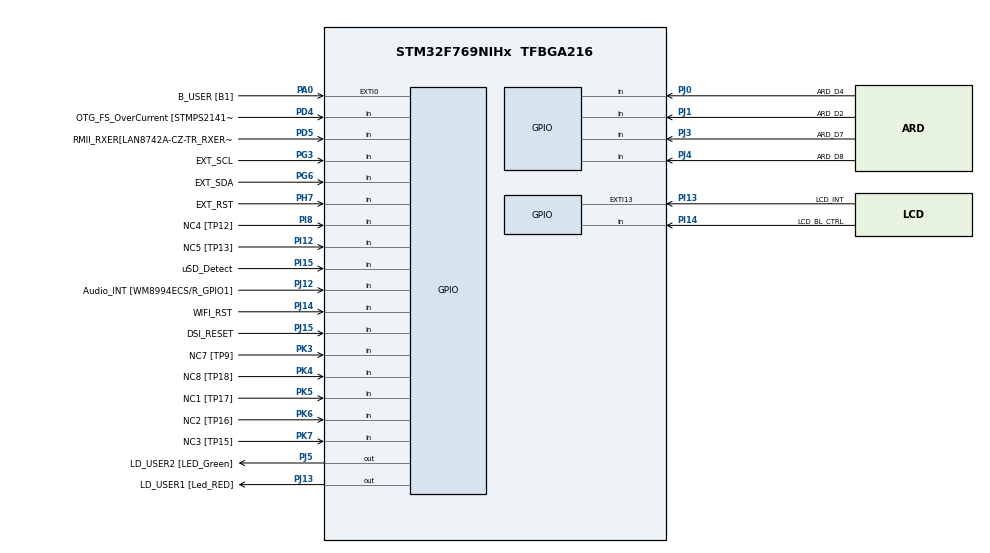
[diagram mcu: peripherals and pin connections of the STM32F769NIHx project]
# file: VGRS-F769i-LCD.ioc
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DSIHOST_CKN.GPIO_Label=DSI_CK_N
DSIHOST_CKN.Signal=DSIHOST_CKN
DSIHOST_CKP.GPIO_Label=DSI_CK_P
DSIHOST_CKP.Signal=DSIHOST_CKP
DSIHOST_D0N.GPIO_Label=DSI_D0_N
DSIHOST_D0N.Signal=DSIHOST_D0N
DSIHOST_D0P.GPIO_Label=DSI_D0_p
DSIHOST_D0P.Signal=DSIHOST_D0P
DSIHOST_D1N.GPIO_Label=DSI_D1_N
DSIHOST_D1N.Signal=DSIHOST_D1N
DSIHOST_D1P.GPIO_Label=DSI_D1_P
DSIHOST_D1P.Signal=DSIHOST_D1P
FREERTOS.Tasks01=defaultTask,24,512,StartDefaultTask,Default,NULL,Dynamic,NULL,NULL
FREERTOS.configMINIMAL_STACK_SIZE=512
Mcu.Family=STM32F7
Mcu.Name=STM32F769NIHx
Mcu.Package=TFBGA216
NVIC.PriorityGroup=NVIC_PRIORITYGROUP_4
PA0/WKUP.GPIO_Label=B_USER [B1]
PA0/WKUP.Signal=GPXTI0
PA1.GPIO_Label=RMII_REF_CLK [LAN8742A-CZ-TR_REFCLK0]
PA1.Signal=ETH_REF_CLK
PA10.GPIO_Label=VCP_RX 
PA10.Signal=USART1_RX
PA11.GPIO_Label=SPI2_NSS
PA11.Signal=SPI2_NSS
PA12.GPIO_Label=ARD_D13/SCK
PA12.GPIO_Mode=GPIO_MODE_AF_PP
PA12.GPIO_PuPd=GPIO_NOPULL
PA12.GPIO_Speed=GPIO_SPEED_FREQ_LOW
PA12.Signal=SPI2_SCK
PA13.GPIO_Label=SWDIO
PA13.Signal=SYS_JTMS-SWDIO
PA14.GPIO_Label=SWCLK
PA14.Signal=SYS_JTCK-SWCLK
PA15.GPIO_Label=CEC
PA15.Signal=CEC
PA2.GPIO_Label=RMII_MDIO [LAN8742A-CZ-TR_MDIO]
PA2.Signal=ETH_MDIO
PA3.GPIO_Label=ULPI_D0 [USB3320C-EZK_D0]
PA3.Signal=USB_OTG_HS_ULPI_D0
PA4.GPIO_Label=ARD_A1
PA4.Signal=ADCx_IN4
PA5.GPIO_Label=ULPI_CLK [USB3320C-EZK_CLKOUT]
PA5.Signal=USB_OTG_HS_ULPI_CK
PA6.GPIO_Label=ARD_A0
PA6.Signal=ADCx_IN6
PA7.GPIO_Label=RMII_CRS_DV [LAN8742A-CZ-TR_CRS_DV]
PA7.Signal=ETH_CRS_DV
PA8.GPIO_Label=CEC_CLK [TP2]
PA8.Signal=RCC_MCO_1
PA9.GPIO_Label=VCP_TX [STM32F103CBT6_PA3]
PA9.GPIO_Mode=GPIO_MODE_AF_PP
PA9.GPIO_PuPd=GPIO_NOPULL
PA9.GPIO_Speed=GPIO_SPEED_FREQ_LOW
PA9.Signal=USART1_TX
PB0.GPIO_Label=ULPI_D1 [USB3320C-EZK_D1]
PB0.Signal=USB_OTG_HS_ULPI_D1
PB1.GPIO_Label=ULPI_D2 [USB3320C-EZK_D2]
PB1.Signal=USB_OTG_HS_ULPI_D2
PB10.GPIO_Label=ULPI_D3 [USB3320C-EZK_D3]
PB10.Signal=USB_OTG_HS_ULPI_D3
PB11.GPIO_Label=ULPI_D4 [USB3320C-EZK_D4]
PB11.Signal=USB_OTG_HS_ULPI_D4
PB12.GPIO_Label=ULPI_D5 [USB3320C-EZK_D5]
PB12.Signal=USB_OTG_HS_ULPI_D5
PB13.GPIO_Label=ULPI_D6 [USB3320C-EZK_D6]
PB13.Signal=USB_OTG_HS_ULPI_D6
PB14.GPIO_Label=ARDUINO MISO/D12
PB14.GPIO_Mode=GPIO_MODE_AF_PP
PB14.GPIO_PuPd=GPIO_NOPULL
PB14.GPIO_Speed=GPIO_SPEED_FREQ_LOW
PB14.Signal=SPI2_MISO
PB15.GPIO_Label=ARDUINO MOSI/PWM/D11
PB15.GPIO_Mode=GPIO_MODE_AF_PP
PB15.GPIO_PuPd=GPIO_NOPULL
PB15.GPIO_Speed=GPIO_SPEED_FREQ_LOW
PB15.Signal=SPI2_MOSI
PB2.Signal=QUADSPI_CLK
PB3.GPIO_Label=uSD_D2
PB3.Signal=SDMMC2_D2
PB4.GPIO_Label=uSD_D3
PB4.Signal=SDMMC2_D3
PB5.GPIO_Label=ULPI_D7 [USB3320C-EZK_D7]
PB5.Signal=USB_OTG_HS_ULPI_D7
PB6.GPIO_Label=QSPI_NCS [N25Q128A13EF840E_S]
PB6.Signal=QUADSPI_BK1_NCS
PB7.GPIO_Label=AUDIO_SDA [WM8994ECS/R_SDA]
PB7.Signal=I2C4_SDA
PB8.GPIO_Label=ARDUINO SCL/D15
PB8.GPIO_Mode=GPIO_MODE_AF_OD
PB8.GPIO_PuPd=GPIO_NOPULL
PB8.GPIO_Speed=GPIO_SPEED_FREQ_LOW
PB8.Signal=I2C1_SCL
PB9.GPIO_Label=ARDUINO SDA/D14
PB9.GPIO_Mode=GPIO_MODE_AF_OD
PB9.GPIO_PuPd=GPIO_NOPULL
PB9.GPIO_Speed=GPIO_SPEED_FREQ_LOW
PB9.Signal=I2C1_SDA
PC0.GPIO_Label=ULPI_STP [USB3320C-EZK_STP]
PC0.Signal=USB_OTG_HS_ULPI_STP
PC1.GPIO_Label=RMII_MDC [LAN8742A-CZ-TR_MDC]
PC1.Signal=ETH_MDC
PC10.GPIO_Label=QSPI_D1 [MT25QL512ABB1EW9_DQ1]
PC10.Signal=QUADSPI_BK1_IO1
PC11.GPIO_Label=DFSDM_DATIN5 [TP100]
PC11.Signal=S_DATAIN5DFSDM1
PC12.GPIO_Label=WIFI_RX
PC12.Signal=UART5_TX
PC14/OSC32_IN.GPIO_Label=RCC_OSC32_IN
PC14/OSC32_IN.Signal=RCC_OSC32_IN
PC15/OSC32_OUT.GPIO_Label=RCC_OSC32_OUT
PC15/OSC32_OUT.Signal=RCC_OSC32_OUT
PC2.GPIO_Label=ARD_A2
PC2.Signal=ADCx_IN12
PC3.GPIO_Label=DFSDM_DATIN1 [TP101]
PC3.Signal=S_DATAIN1DFSDM1
PC4.GPIO_Label=RMII_RXD0 [LAN8742A-CZ-TR_RXD0]
PC4.Signal=ETH_RXD0
PC5.GPIO_Label=RMII_RXD1 [LAN8742A-CZ-TR_RXD1]
PC5.Signal=ETH_RXD1
PC6.GPIO_Label=ARDUINO TX/D1
PC6.Signal=USART6_TX
PC7.GPIO_Label=ARD_D0/RX
PC7.Signal=USART6_RX
PC8.GPIO_Label=ARD_D5/PWM
PC8.Signal=S_TIM3_CH3
PC9.GPIO_Label=QSPI_D0 [N25Q128A13EF840E_DQ0]
PC9.Signal=QUADSPI_BK1_IO0
PD0.GPIO_Label=FMC_D2 [MT48LC4M32B2B5-6A_DQ2]
PD0.Signal=FMC_D2_DA2
PD1.GPIO_Label=FMC_D3 [MT48LC4M32B2B5-6A_DQ3]
PD1.Signal=FMC_D3_DA3
PD10.GPIO_Label=FMC_D15 [MT48LC4M32B2B5-6A_DQ15]
PD10.Signal=FMC_D15_DA15
PD11.GPIO_Label=SPDIF_TX [TP20]
PD11.Signal=SAI2_SD_A
PD12.GPIO_Label=AUDIO_SCL [WM8994ECS/R_SCLK]
PD12.Signal=I2C4_SCL
PD13.GPIO_Label=QSPI_D3 [N25Q128A13EF840E_DQ3]
PD13.Signal=QUADSPI_BK1_IO3
PD14.GPIO_Label=FMC_D0 [MT48LC4M32B2B5-6A_DQ0]
PD14.Signal=FMC_D0_DA0
PD15.GPIO_Label=FMC_D1 [MT48LC4M32B2B5-6A_DQ1]
PD15.Signal=FMC_D1_DA1
PD2.GPIO_Label=WIFI_TX
PD2.Signal=UART5_RX
PD3.GPIO_Label=DFSDM_CKOUT [TP102]
PD3.Signal=S_CKOUTDFSDM1
PD4.GPIO_Label=OTG_FS_OverCurrent [STMPS2141STR_Fault]
PD4.Signal=GPIO_Input
PD5.GPIO_Label=RMII_RXER[LAN8742A-CZ-TR_RXERR]
PD5.Signal=GPIO_Input
PD6.GPIO_Label=uSD_CLK
PD6.Signal=SDMMC2_CK
PD7.GPIO_Label=uSD_CMD
PD7.Signal=SDMMC2_CMD
PD8.GPIO_Label=FMC_D13 [MT48LC4M32B2B5-6A_DQ13]
PD8.Signal=FMC_D13_DA13
PD9.GPIO_Label=FMC_D14 [MT48LC4M32B2B5-6A_DQ14]
PD9.Signal=FMC_D14_DA14
PE0.GPIO_Label=FMC_NBL0 [MT48LC4M32B2B5-6A_DQM0]
PE0.Signal=FMC_NBL0
PE1.GPIO_Label=FMC_NBL1 [MT48LC4M32B2B5-6A_DQM1]
PE1.Signal=FMC_NBL1
PE10.GPIO_Label=FMC_D7 [MT48LC4M32B2B5-6A_DQ7]
PE10.Signal=FMC_D7_DA7
PE11.GPIO_Label=FMC_D8 [MT48LC4M32B2B5-6A_DQ8]
PE11.Signal=FMC_D8_DA8
PE12.GPIO_Label=FMC_D9 [MT48LC4M32B2B5-6A_DQ9]
PE12.Signal=FMC_D9_DA9
PE13.GPIO_Label=FMC_D10 [MT48LC4M32B2B5-6A_DQ10]
PE13.Signal=FMC_D10_DA10
PE14.GPIO_Label=FMC_D11 [MT48LC4M32B2B5-6A_DQ11]
PE14.Signal=FMC_D11_DA11
PE15.GPIO_Label=FMC_D12 [MT48LC4M32B2B5-6A_DQ12]
PE15.Signal=FMC_D12_DA12
PE2.GPIO_Label=QSPI_D2 [N25Q128A13EF840E_DQ2]
PE2.Signal=QUADSPI_BK1_IO2
PE3.GPIO_Label=SAI1_SDB [WM8994ECS/R_ADCDAT1]
PE3.Signal=SAI1_SD_B
PE4.GPIO_Label=SAI1_FSA [WM8994ECS/R_LRCLK1]
PE4.Signal=SAI1_FS_A
PE5.GPIO_Label=SAI1_SCKA [WM8994ECS/R_BCLK1]
PE5.Signal=SAI1_SCK_A
PE6.GPIO_Label=SAI1_SDA [WM8994ECS/R_DACDAT1]
PE6.Signal=SAI1_SD_A
PE7.GPIO_Label=FMC_D4 [MT48LC4M32B2B5-6A_DQ4]
PE7.Signal=FMC_D4_DA4
PE8.GPIO_Label=FMC_D5 [MT48LC4M32B2B5-6A_DQ5]
PE8.Signal=FMC_D5_DA5
PE9.GPIO_Label=FMC_D6 [MT48LC4M32B2B5-6A_DQ6]
PE9.Signal=FMC_D6_DA6
PF0.GPIO_Label=FMC_A0 [MT48LC4M32B2B5-6A_A0]
PF0.Signal=FMC_A0
PF1.GPIO_Label=FMC_A1 [MT48LC4M32B2B5-6A_A1]
PF1.Signal=FMC_A1
PF10.GPIO_Label=ARDUINO A1
PF10.GPIO_Mode=GPIO_MODE_ANALOG
PF10.GPIO_PuPd=GPIO_NOPULL
PF10.Signal=ADC3_IN8
PF11.GPIO_Label=FMC_SDNRAS [MT48LC4M32B2B5-6A_RAS]
PF11.Signal=FMC_SDNRAS
PF12.GPIO_Label=FMC_A6 [MT48LC4M32B2B5-6A_A6]
PF12.Signal=FMC_A6
PF13.GPIO_Label=FMC_A7 [MT48LC4M32B2B5-6A_A7]
PF13.Signal=FMC_A7
PF14.GPIO_Label=FMC_A8 [MT48LC4M32B2B5-6A_A8]
PF14.Signal=FMC_A8
PF15.GPIO_Label=FMC_A9 [MT48LC4M32B2B5-6A_A9]
PF15.Signal=FMC_A9
PF2.GPIO_Label=FMC_A2 [MT48LC4M32B2B5-6A_A2]
PF2.Signal=FMC_A2
PF3.GPIO_Label=FMC_A3 [MT48LC4M32B2B5-6A_A3]
PF3.Signal=FMC_A3
PF4.GPIO_Label=FMC_A4 [MT48LC4M32B2B5-6A_A4]
PF4.Signal=FMC_A4
PF5.GPIO_Label=FMC_A5 [MT48LC4M32B2B5-6A_A5]
PF5.Signal=FMC_A5
PF6.GPIO_Label=ARD_D3/PWM
PF6.Signal=S_TIM10_CH1
PF7.GPIO_Label=ARD_D6/PWM
PF7.Signal=S_TIM11_CH1
PF8.GPIO_Label=ARDUINO A3
PF8.GPIO_Mode=GPIO_MODE_ANALOG
PF8.GPIO_PuPd=GPIO_NOPULL
PF8.Signal=ADC3_IN6
PF9.GPIO_Label=ARDUINO A2
PF9.GPIO_Mode=GPIO_MODE_ANALOG
PF9.GPIO_PuPd=GPIO_NOPULL
PF9.Signal=ADC3_IN7
PG0.GPIO_Label=FMC_A10 [MT48LC4M32B2B5-6A_A10]
PG0.Signal=FMC_A10
PG1.GPIO_Label=FMC_A11 [MT48LC4M32B2B5-6A_A11]
PG1.Signal=FMC_A11
PG10.GPIO_Label=uSD_D1
PG10.Signal=SDMMC2_D1
PG11.GPIO_Label=RMII_TX_EN [LAN8742A-CZ-TR_TXEN]
PG11.Signal=ETH_TX_EN
PG12.GPIO_Label=SPDIF_RX [74LVC1G04SE_4]
PG12.Signal=SPDIFRX_IN1
PG13.GPIO_Label=RMII_TXD0 [LAN8742A-CZ-TR_TXD0]
PG13.Signal=ETH_TXD0
PG14.GPIO_Label=RMII_TXD1 [LAN8742A-CZ-TR_TXD1]
PG14.Signal=ETH_TXD1
PG15.GPIO_Label=FMC_SDNCAS [MT48LC4M32B2B5-6A_CAS]
PG15.Signal=FMC_SDNCAS
PG2.GPIO_Label=FMC_A12
PG2.Signal=FMC_A12
PG3.GPIO_Label=EXT_SCL
PG3.Signal=GPIO_Input
PG4.GPIO_Label=FMC_BA0 [MT48LC4M32B2B5-6A_BA0]
PG4.Signal=FMC_A14_BA0
PG5.GPIO_Label=FMC_BA1 [MT48LC4M32B2B5-6A_BA1]
PG5.Signal=FMC_A15_BA1
PG6.GPIO_Label=EXT_SDA
PG6.Signal=GPIO_Input
PG7.GPIO_Label=SAI1_MCLKA [WM8994ECS/R_MCLK1]
PG7.Signal=SAI1_MCLK_A
PG8.GPIO_Label=FMC_SDCLK [MT48LC4M32B2B5-6A_CLK]
PG8.Signal=FMC_SDCLK
PG9.GPIO_Label=uSD_D0
PG9.Signal=SDMMC2_D0
PH0/OSC_IN.GPIO_Label=OSC_25M [NZ2520SB-25.00M_OUT]
PH0/OSC_IN.Signal=RCC_OSC_IN
PH1/OSC_OUT.Signal=RCC_OSC_OUT
PH10.GPIO_Label=FMC_D18 [MT48LC4M32B2B5-6A_DQ18]
PH10.Signal=FMC_D18
PH11.GPIO_Label=FMC_D19 [MT48LC4M32B2B5-6A_DQ19]
PH11.Signal=FMC_D19
PH12.GPIO_Label=D20
PH12.Signal=FMC_D20
PH13.GPIO_Label=D21
PH13.Signal=FMC_D21
PH14.GPIO_Label=D22
PH14.Signal=FMC_D22
PH15.GPIO_Label=D23
PH15.Signal=FMC_D23
PH2.GPIO_Label=FMC_SDCKE0 [MT48LC4M32B2B5-6A_CKE]
PH2.Signal=FMC_SDCKE0
PH3.GPIO_Label=FMC_SDNE0 [MT48LC4M32B2B5-6A_CS]
PH3.Signal=FMC_SDNE0
PH4.GPIO_Label=ULPI_NXT [USB3320C-EZK_NXT]
PH4.Signal=USB_OTG_HS_ULPI_NXT
PH5.GPIO_Label=FMC_SDNME [MT48LC4M32B2B5-6A_WE]
PH5.Signal=FMC_SDNWE
PH6.GPIO_Label=ARDUINO PWM/D6
PH6.Signal=S_TIM12_CH1
PH7.GPIO_Label=EXT_RST
PH7.Signal=GPIO_Input
PH8.GPIO_Label=FMC_D16 [MT48LC4M32B2B5-6A_DQ16]
PH8.Signal=FMC_D16
PH9.GPIO_Label=FMC_D\!7 [MT48LC4M32B2B5-6A_DQ17]
PH9.Signal=FMC_D17
PI0.GPIO_Label=D24
PI0.Signal=FMC_D24
PI1.GPIO_Label=D25
PI1.Signal=FMC_D25
PI10.GPIO_Label=D31
PI10.Signal=FMC_D31
PI11.GPIO_Label=ULPI_DIR [USB3320C-EZK_DIR]
PI11.Signal=USB_OTG_HS_ULPI_DIR
PI12.GPIO_Label=NC5 [TP13]
PI12.Signal=GPIO_Input
PI13.GPIO_Label=LCD_INT
PI13.GPIO_ModeDefaultEXTI=GPIO_MODE_EVT_RISING
PI13.Signal=GPXTI13
PI14.GPIO_Label=LCD_BL_CTRL
PI14.Signal=GPIO_Input
PI15.GPIO_Label=uSD_Detect
PI15.Signal=GPIO_Input
PI2.GPIO_Label=D26
PI2.Signal=FMC_D26
PI3.GPIO_Label=D27
PI3.Signal=FMC_D27
PI4.GPIO_Label=FMC_NBL2 [MT48LC4M32B2B5-6A_DQM2]
PI4.Signal=FMC_NBL2
PI5.GPIO_Label=FMC_NBL3 [MT48LC4M32B2B5-6A_DQM3]
PI5.Signal=FMC_NBL3
PI6.GPIO_Label=D28
PI6.Signal=FMC_D28
PI7.GPIO_Label=D29
PI7.Signal=FMC_D29
PI8.GPIO_Label=NC4 [TP12]
PI8.Signal=GPIO_Input
PI9.GPIO_Label=D30
PI9.Signal=FMC_D30
PJ0.GPIO_Label=ARD_D4
PJ0.Signal=GPIO_Input
PJ1.GPIO_Label=ARD_D2
PJ1.Signal=GPIO_Input
PJ12.GPIO_Label=Audio_INT [WM8994ECS/R_GPIO1]
PJ12.Signal=GPIO_Input
PJ13.GPIO_Label=LD_USER1 [Led_RED]
PJ13.Signal=GPIO_Output
PJ14.GPIO_Label=WIFI_RST
PJ14.Signal=GPIO_Input
PJ15.GPIO_Label=DSI_RESET
PJ15.Signal=GPIO_Input
PJ2.GPIO_Label=DSIHOST_TE
PJ2.Signal=DSIHOST_TE
PJ3.GPIO_Label=ARD_D7
PJ3.Signal=GPIO_Input
PJ4.GPIO_Label=ARD_D8
PJ4.Signal=GPIO_Input
PJ5.GPIO_Label=LD_USER2 [LED_Green]
PJ5.Signal=GPIO_Output
PK3.GPIO_Label=NC7 [TP9]
PK3.Signal=GPIO_Input
PK4.GPIO_Label=NC8 [TP18]
PK4.Signal=GPIO_Input
PK5.GPIO_Label=NC1 [TP17]
PK5.Signal=GPIO_Input
PK6.GPIO_Label=NC2 [TP16]
PK6.Signal=GPIO_Input
PK7.GPIO_Label=NC3 [TP15]
PK7.Signal=GPIO_Input
ProjectManager.HeapSize=0x200
ProjectManager.StackSize=0x400
ProjectManager.TargetToolchain=STM32CubeIDE
RCC.AHBFreq_Value=96000000
RCC.APB1CLKDivider=RCC_HCLK_DIV4
RCC.APB1Freq_Value=24000000
RCC.APB1TimFreq_Value=48000000
RCC.APB2CLKDivider=RCC_HCLK_DIV2
RCC.APB2Freq_Value=48000000
RCC.APB2TimFreq_Value=96000000
RCC.CortexFreq_Value=96000000
RCC.HCLKFreq_Value=96000000
RCC.HSE_VALUE=25000000
RCC.HSI_VALUE=16000000
RCC.LSE_VALUE=32768
RCC.PLLM=8
RCC.PLLP=RCC_PLLP_DIV4
RCC.PLLQ=4
RCC.PLLSAIQ=3
RCC.SYSCLKFreq_VALUE=96000000
RCC.SYSCLKSource=RCC_SYSCLKSOURCE_PLLCLK
RCC.USBFreq_Value=96000000
RCC.VCOOutputFreq_Value=384000000
SH.ADCx_IN12.0=ADC1_IN12
SH.ADCx_IN4.0=ADC1_IN4
SH.ADCx_IN6.0=ADC1_IN6
SH.FMC_A0.0=FMC_A0
SH.FMC_A1.0=FMC_A1
SH.FMC_A10.0=FMC_A10
SH.FMC_A11.0=FMC_A11
SH.FMC_A12.0=FMC_A12
SH.FMC_A14_BA0.0=FMC_BA0
SH.FMC_A15_BA1.0=FMC_BA1
SH.FMC_A2.0=FMC_A2
SH.FMC_A3.0=FMC_A3
SH.FMC_A4.0=FMC_A4
SH.FMC_A5.0=FMC_A5
SH.FMC_A6.0=FMC_A6
SH.FMC_A7.0=FMC_A7
SH.FMC_A8.0=FMC_A8
SH.FMC_A9.0=FMC_A9
SH.FMC_D0_DA0.0=FMC_D0
SH.FMC_D10_DA10.0=FMC_D10
SH.FMC_D11_DA11.0=FMC_D11
SH.FMC_D12_DA12.0=FMC_D12
SH.FMC_D13_DA13.0=FMC_D13
SH.FMC_D14_DA14.0=FMC_D14
SH.FMC_D15_DA15.0=FMC_D15
SH.FMC_D16.0=FMC_D16
SH.FMC_D17.0=FMC_D17
SH.FMC_D18.0=FMC_D18
SH.FMC_D19.0=FMC_D19
SH.FMC_D1_DA1.0=FMC_D1
SH.FMC_D20.0=FMC_D20
SH.FMC_D21.0=FMC_D21
SH.FMC_D22.0=FMC_D22
SH.FMC_D23.0=FMC_D23
SH.FMC_D24.0=FMC_D24
SH.FMC_D25.0=FMC_D25
SH.FMC_D26.0=FMC_D26
SH.FMC_D27.0=FMC_D27
SH.FMC_D28.0=FMC_D28
SH.FMC_D29.0=FMC_D29
SH.FMC_D2_DA2.0=FMC_D2
SH.FMC_D30.0=FMC_D30
SH.FMC_D31.0=FMC_D31
SH.FMC_D3_DA3.0=FMC_D3
SH.FMC_D4_DA4.0=FMC_D4
SH.FMC_D5_DA5.0=FMC_D5
SH.FMC_D6_DA6.0=FMC_D6
SH.FMC_D7_DA7.0=FMC_D7
SH.FMC_D8_DA8.0=FMC_D8
SH.FMC_D9_DA9.0=FMC_D9
SH.FMC_NBL0.0=FMC_NBL0
SH.FMC_NBL1.0=FMC_NBL1
SH.FMC_NBL2.0=FMC_NBL2
SH.FMC_NBL3.0=FMC_NBL3
SH.FMC_SDCLK.0=FMC_SDCLK
SH.FMC_SDNCAS.0=FMC_SDNCAS
SH.FMC_SDNRAS.0=FMC_SDNRAS
SH.FMC_SDNWE.0=FMC_SDNWE
SH.S_CKOUTDFSDM1.0=DFSDM1_CKOUT
SH.S_DATAIN1DFSDM1.0=DFSDM1_DATIN1
SH.S_DATAIN5DFSDM1.0=DFSDM1_DATIN5
SH.S_TIM10_CH1.0=TIM10_CH1
SH.S_TIM11_CH1.0=TIM11_CH1
SH.S_TIM12_CH1.0=TIM12_CH1
SH.S_TIM3_CH3.0=TIM3_CH3
VP_FREERTOS_VS_CMSIS_V2.Mode=CMSIS_V2
board=STM32F769I-DISCO

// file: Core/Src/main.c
/* USER CODE BEGIN Header */
/**
  ******************************************************************************
  * @file           : main.c
  * @brief          : Main program body
  ******************************************************************************
  * @attention
  *
  * Copyright (c) 2022 STMicroelectronics.
  * All rights reserved.
  *
  * This software is licensed under terms that can be found in the LICENSE file
  * in the root directory of this software component.
  * If no LICENSE file comes with this software, it is provided AS-IS.
  *
  ******************************************************************************
  */
/* USER CODE END Header */
#include "main.h"

/* USER CODE BEGIN Includes */
#include "stlogo.h"
#include "pa3SDRAM.h"
#include "cmsis_os.h"
#include "pa3Timers.h"
#include "uart.h"
#include "dma.h"
#include "can.h"
#include "obd2.h"
#include "retarget.h"
/* USER CODE END Includes */

/* USER CODE BEGIN PD */
//#define __MEASURE__
#ifdef __MEASURE__
#define __DELAY 2
#else
#define __DELAY 100
#endif
/* USER CODE END PD */

/* Definitions for defaultTask */
osThreadId_t defaultTaskHandle;
const osThreadAttr_t defaultTask_attributes = {
  .name = "defaultTask",
  .stack_size = 512 * 4,
  .priority = (osPriority_t) osPriorityNormal,
};
/* USER CODE BEGIN PV */
__IO uint8_t DemoIndex = 0;
__IO uint8_t NbLoop = 1;
__IO uint32_t SdmmcTest = 0;
__IO uint32_t SdramTest = 0;

osThreadId_t Task1Handle;
const osThreadAttr_t Task1_attributes = {
  .name = "Task 1",
  .stack_size = 512 * 4,
  .priority = (osPriority_t) osPriorityNormal,
};

osThreadId_t Task2Handle;
const osThreadAttr_t Task2_attributes = {
  .name = "Task 2",
  .stack_size = 512 * 4,
  .priority = (osPriority_t) osPriorityNormal,
};

osMessageQueueId_t mid_MsgQueue;                // message queue id

TIM_HandleTypeDef    	TIM3Handle;
uint16_t timer_val_start, timer_val_end;
uint16_t elapsed_rows, elapsed_cols, elapsed_dma;

UART_HandleTypeDef 		UART1Handle;
DMA_HandleTypeDef    	DMA2_SDRAM_Handle;
extern SDRAM_HandleTypeDef 			sdramHand;

int count = 0;
osMutexId_t  mutex;

extern ALIGN_32BYTES (uint32_t sdram_read_Buffer[SDRAM_BUFFER_SIZE]);

/* USER CODE END PV */

void SystemClock_Config(void);
//static void MX_GPIO_Init(void);
void StartDefaultTask(void *argument);
static void MPU_Config(void);
void SystemClock_Config(void);
//static void Display_DemoDescription(void);
static void CPU_CACHE_Enable(void);

/* USER CODE BEGIN PFP */
void Task1(void *argument);
void Task2(void *argument);
/* USER CODE END PFP */

int main(void)
{
  /* USER CODE BEGIN 1 */
  uint8_t  lcd_status = LCD_OK;
  char time_str1[40];
  char time_str2[20];

  /* Configure the MPU attributes */
  MPU_Config();

  /* Enable the CPU Cache */
  CPU_CACHE_Enable();
  /* USER CODE END 1 */

  /* MCU Configuration--------------------------------------------------------*/

  /* Reset of all peripherals, Initializes the Flash interface and the Systick. */
  HAL_Init();

  /* Configure the system clock */
  SystemClock_Config();

  /* Initialize all configured peripherals */
  //MX_GPIO_Init();
  /* USER CODE BEGIN 2 */
  BSP_LED_Init(LED_GREEN);
  BSP_LED_Init(LED_RED);

  BSP_LED_Off(LED_GREEN);
  BSP_LED_Off(LED_RED);

  HAL_GPIO_WritePin(GPIOC, GPIO_PIN_8, GPIO_PIN_RESET);

    /* Init timers */
#ifdef __USE_TIM3_BASE__
  Init_TIM3(&TIM3Handle);
#endif

  /* Configure the Tamper push-button in GPIO Mode */
  BSP_PB_Init(BUTTON_WAKEUP, BUTTON_MODE_GPIO);

  //if (CAN_Config_LoopBack() != HAL_OK) {
  if (CAN1_Config(CAN_LOOPBACK_MODE) != HAL_OK) {
	  Error_Handler();
  }
  //CAN_SendReceiveMessage();
  //OBD2_SendQuery(0x01, OBD2_PID_VEHICLE_SPEED);
  //OBD2_ReceiveData();

  /* Init UART1*/
  if (USART1_Init(&UART1Handle) != HAL_OK){
	  Error_Handler();
  }
  RetargetInit(&UART1Handle);

  // Configure DMA2 for UART1:
  if (DMA2_UART1_Config() != HAL_OK) {
	  Error_Handler();
  }

  // Configure DMA2 for SDRAM:
  if (DMA2_SDRAM_Config(&DMA2_SDRAM_Handle) != HAL_OK) {
	  Error_Handler();
  }
  // Link DMA2_SDRAM_Handle to DMA handle field in SDRAM handle
  __HAL_LINKDMA(&sdramHand, hdma, DMA2_SDRAM_Handle);

  /* Initialize the LCD */
  lcd_status = BSP_LCD_Init();
  while(lcd_status != LCD_OK);

  BSP_LCD_LayerDefaultInit(0, LCD_FB_START_ADDRESS);

  BSP_LCD_ReadPixel(BSP_LCD_GetXSize()-1, BSP_LCD_GetYSize()-1);

  BSP_LCD_Clear(LCD_COLOR_WHITE);
  /* Set LCD Foreground Layer  */
  BSP_LCD_SelectLayer(0);
  BSP_LCD_SetFont(&LCD_DEFAULT_FONT);
  /* Clear the LCD */
  BSP_LCD_SetBackColor(LCD_COLOR_BLACK);
  BSP_LCD_Clear(LCD_COLOR_WHITE);
  BSP_LCD_Clear(LCD_COLOR_BLACK);
  /* Set the LCD Text Color */
  //BSP_LCD_SetTextColor(LCD_COLOR_DARKBLUE);
  BSP_LCD_SetTextColor(LCD_COLOR_WHITE);
  /* Display LCD messages */
  BSP_LCD_DisplayStringAt(0, 10+20, (uint8_t *)"STM32F769I BSP", CENTER_MODE);
#ifdef __VGRS__
  BSP_LCD_DisplayStringAt(0, 35+20, (uint8_t *)"Vgrajeni sistemi 2022", CENTER_MODE);
#endif
#ifdef __ORS__
  BSP_LCD_DisplayStringAt(0, 35+20, (uint8_t *)"Organizacija racunalniskih sistemov 2022", CENTER_MODE);
#endif

#ifdef __ORS__

  Init_SDRAM();
  simple_SDRAM_test();

  BSP_LCD_SetTextColor(LCD_COLOR_GREEN);
  BSP_LCD_DisplayStringAt(30, 95+80, (uint8_t *)"Vsebina v SDRAM:", LEFT_MODE);
  BSP_LCD_SetTextColor(LCD_COLOR_RED);
  BSP_LCD_DisplayStringAt(60, 120+80, (uint8_t *)sdram_read_Buffer, LEFT_MODE);

  //HAL_UART_Transmit(&UART1Handle, (uint8_t *)"STM32F769I \n", strlen("STM32F769I \n"), HAL_MAX_DELAY);
  //HAL_UART_Transmit(&UART1Handle, (uint8_t *)"Vsebina v SDRAM: ", strlen("Vsebina v SDRAM: "), HAL_MAX_DELAY);
  //HAL_UART_Transmit(&UART1Handle, (uint8_t *)sdram_read_Buffer, strlen(sdram_read_Buffer), HAL_MAX_DELAY);
  printf("STM32F769I BSP \n");
  printf("Organizacija racunalniskih sistemov 2022 \n");
  printf("Vsebina v SDRAM:  \n");
  printf("%s", sdram_read_Buffer);

  HAL_Delay(500);
  SDRAM_init_matrices();
  SDRAM_write_matrix();

  while (1){

	  // Row-major order access:
	  HAL_GPIO_WritePin(GPIOC, GPIO_PIN_8, GPIO_PIN_SET);
	  timer_val_start = __HAL_TIM_GET_COUNTER(&TIM3Handle);
	  SDRAM_mat_row_access_test();
	  timer_val_end = __HAL_TIM_GET_COUNTER(&TIM3Handle);
	  HAL_GPIO_WritePin(GPIOC, GPIO_PIN_8, GPIO_PIN_RESET);

	  if (timer_val_end > timer_val_start)
		  elapsed_rows = timer_val_end - timer_val_start;
	  else
		  elapsed_rows = timer_val_end + (65536-timer_val_start);

	  if (SDRAM_compare_matrices()==0) {
		  BSP_LED_On(LED_GREEN);
	  	  HAL_Delay(__DELAY);
	  }
	  else Error_Handler();
	  BSP_LED_Off(LED_GREEN);

	  // column-major order access:
	  HAL_GPIO_WritePin(GPIOC, GPIO_PIN_8, GPIO_PIN_SET);
	  timer_val_start = __HAL_TIM_GET_COUNTER(&TIM3Handle);
	  SDRAM_mat_col_access_test();
	  timer_val_end = __HAL_TIM_GET_COUNTER(&TIM3Handle);
	  HAL_GPIO_WritePin(GPIOC, GPIO_PIN_8, GPIO_PIN_RESET);

	  if (timer_val_end > timer_val_start)
		  elapsed_cols = timer_val_end - timer_val_start;
	  else
		  elapsed_cols = timer_val_end + (65536-timer_val_start);

	  if (SDRAM_compare_matrices()==0) {
		  BSP_LED_On(LED_RED);
	  	  HAL_Delay(__DELAY);
	  }
	  else Error_Handler();
	  BSP_LED_Off(LED_RED);

	  // row-major access using DMA:
	  HAL_GPIO_WritePin(GPIOC, GPIO_PIN_8, GPIO_PIN_SET);
	  timer_val_start = __HAL_TIM_GET_COUNTER(&TIM3Handle);
	  SDRAM_DMA_mat_row_access_test();
	  timer_val_end = __HAL_TIM_GET_COUNTER(&TIM3Handle);
	  HAL_GPIO_WritePin(GPIOC, GPIO_PIN_8, GPIO_PIN_RESET);

	  if (timer_val_end > timer_val_start)
		  elapsed_dma = timer_val_end - timer_val_start;
	  else
		  elapsed_dma = timer_val_end + (65536-timer_val_start);

	  if (SDRAM_compare_matrices()==0) {
		  BSP_LED_On(LED_RED);
		  BSP_LED_On(LED_GREEN);
	  	  HAL_Delay(__DELAY);
	  }
	  else Error_Handler();
	  BSP_LED_Off(LED_RED);
	  BSP_LED_Off(LED_GREEN);

	  BSP_LCD_SetTextColor(LCD_COLOR_BLUE);
	  BSP_LCD_FillRect(0, BSP_LCD_GetYSize()/2 + 35, BSP_LCD_GetXSize(), 80);
	  BSP_LCD_SetTextColor(LCD_COLOR_WHITE);
	  BSP_LCD_SetBackColor(LCD_COLOR_BLUE);

	  sprintf(time_str1, "Rows:%5dus  ", elapsed_rows);
	  sprintf(time_str2, "Cols:%5dus  ", elapsed_cols);
	  strcat(time_str1, time_str2);
	  sprintf(time_str2, "DMA:%5dus", elapsed_dma);
	  strcat(time_str1, time_str2);
	  BSP_LCD_DisplayStringAt(0, BSP_LCD_GetYSize() / 2 + 50, (uint8_t *)"FMC SDRAM TEST", CENTER_MODE);
	  BSP_LCD_DisplayStringAt(0, BSP_LCD_GetYSize() / 2 + 80, (uint8_t *)time_str1, CENTER_MODE);

	  // Raje uporabi DMA prenos kot pa printf, ki dela na polling
	  //printf("%s \n", time_str1);
	  strcat(time_str1, "  \n");
	  HAL_UART_Transmit_DMA(&UART1Handle, (uint8_t *)time_str1, strlen(time_str1));

	  HAL_Delay(__DELAY);

	  SDRAM_write_const();

  }

#endif

  //BSP_LCD_SetFont(&Font16);
  BSP_LCD_SetTextColor(LCD_COLOR_BLUE);
  //BSP_LCD_FillRect(0, BSP_LCD_GetYSize()/2 + 35, BSP_LCD_GetXSize(), 60);
  BSP_LCD_FillRect(0, 100, BSP_LCD_GetXSize()/3-2, 120);
  BSP_LCD_FillRect(0, 220+4, BSP_LCD_GetXSize()/3-2, 120);
  BSP_LCD_FillRect(0, 340+8, BSP_LCD_GetXSize()/3-2, 120);

  BSP_LCD_FillRect(BSP_LCD_GetXSize()/3+2, 100, BSP_LCD_GetXSize()/3-2, 120);
  BSP_LCD_FillRect(BSP_LCD_GetXSize()/3+2, 220+4, BSP_LCD_GetXSize()/3-2, 120);
  BSP_LCD_FillRect(BSP_LCD_GetXSize()/3+2, 340+8, BSP_LCD_GetXSize()/3-2, 120);

  BSP_LCD_FillRect(2*BSP_LCD_GetXSize()/3+2, 100, BSP_LCD_GetXSize()/3-2, 120);
  BSP_LCD_FillRect(2*BSP_LCD_GetXSize()/3+2, 220+4, BSP_LCD_GetXSize()/3-2, 120);
  BSP_LCD_FillRect(2*BSP_LCD_GetXSize()/3+2, 340+8, BSP_LCD_GetXSize()/3-2, 120);

  BSP_LCD_SetTextColor(LCD_COLOR_WHITE);
  BSP_LCD_SetBackColor(LCD_COLOR_BLUE);

  BSP_LCD_DisplayStringAt(90, 105, (uint8_t *)"RPM", LEFT_MODE);
  BSP_LCD_DisplayStringAt(BSP_LCD_GetXSize()/3+2+90, 105, (uint8_t *)"KM/H", LEFT_MODE);
  BSP_LCD_DisplayStringAt(2*BSP_LCD_GetXSize()/3+2+90, 105, (uint8_t *)"LOAD", LEFT_MODE);

  BSP_LCD_DisplayStringAt(35, 105 + 120 + 4, (uint8_t *)"COOLANT TEMP", LEFT_MODE);
  BSP_LCD_DisplayStringAt(BSP_LCD_GetXSize()/3+2+60, 105 + 120+4, (uint8_t *)"OIL TEMP", LEFT_MODE);
  BSP_LCD_DisplayStringAt(2*BSP_LCD_GetXSize()/3+2+60, 105 + 120+4, (uint8_t *)"AIR TEMP", LEFT_MODE);
  //BSP_LCD_DisplayStringAt(0, BSP_LCD_GetYSize() / 2 + 30, (uint8_t *)"Press User button to start :", CENTER_MODE);

  /* USER CODE END 2 */

  /* Init scheduler */
  osKernelInitialize();

  /* USER CODE BEGIN RTOS_MUTEX */
  mutex = osMutexNew(NULL);
  /* USER CODE END RTOS_MUTEX */

  /* USER CODE BEGIN RTOS_QUEUES */
  mid_MsgQueue = osMessageQueueNew	(16, sizeof(CAN_OBD2_MSGQUEUE_OBJ_t), NULL);
  /* USER CODE END RTOS_QUEUES */

  /* Create the thread(s) */
  /* creation of defaultTask */
  defaultTaskHandle = osThreadNew(StartDefaultTask, NULL, &defaultTask_attributes);

  /* USER CODE BEGIN RTOS_THREADS */
  /* add threads, ... */
  Task1Handle = osThreadNew(Task1, NULL, &Task1_attributes);
  Task2Handle = osThreadNew(Task2, NULL, &Task2_attributes);
  /* USER CODE END RTOS_THREADS */

  /* Start scheduler */
  osKernelStart();

  /* We should never get here as control is now taken by the scheduler */
  /* Infinite loop */
  while (1)
  {

  }
}

/* USER CODE BEGIN 4 */

/**
  * @brief System Clock Configuration
  * @retval None
  */

/**
  * @brief  System Clock Configuration
  *         The system Clock is configured as follow :
  *            System Clock source            = PLL (HSE)
  *            SYSCLK(Hz)                     = 200000000
  *            HCLK(Hz)                       = 200000000
  *            AHB Prescaler                  = 1
  *            APB1 Prescaler                 = 4
  *            APB2 Prescaler                 = 2
  *            HSE Frequency(Hz)              = 25000000
  *            PLL_M                          = 25
  *            PLL_N                          = 400
  *            PLL_P                          = 2
  *            PLL_Q                          = 8
  *            VDD(V)                         = 3.3
  *            Main regulator output voltage  = Scale1 mode
  *            Flash Latency(WS)              = 6
  * @param  None
  * @retval None
  */
void SystemClock_Config(void)
{
  RCC_ClkInitTypeDef RCC_ClkInitStruct;
  RCC_OscInitTypeDef RCC_OscInitStruct;
  HAL_StatusTypeDef ret = HAL_OK;

  /* Enable HSE Oscillator and activate PLL with HSE as source */
  RCC_OscInitStruct.OscillatorType = RCC_OSCILLATORTYPE_HSE; // HSE = 25 MHHz
  RCC_OscInitStruct.HSEState = RCC_HSE_ON;
  RCC_OscInitStruct.PLL.PLLState = RCC_PLL_ON;
  RCC_OscInitStruct.PLL.PLLSource = RCC_PLLSOURCE_HSE;
  RCC_OscInitStruct.PLL.PLLM = 25;	// PLL HSE DIV (1Mhz)
  RCC_OscInitStruct.PLL.PLLN = 400; // PLL MUL (400 MHz)
  RCC_OscInitStruct.PLL.PLLP = RCC_PLLP_DIV2; // (200 MhZ)
  RCC_OscInitStruct.PLL.PLLQ = 8;
  RCC_OscInitStruct.PLL.PLLR = 7;

  ret = HAL_RCC_OscConfig(&RCC_OscInitStruct);
  if(ret != HAL_OK)
  {
    while(1) { ; }
  }

  /* Activate the OverDrive to reach the 200 MHz Frequency */
  ret = HAL_PWREx_EnableOverDrive();
  if(ret != HAL_OK)
  {
    while(1) { ; }
  }

  /* Select PLL as system clock source and configure the HCLK, PCLK1 and PCLK2 clocks dividers */
  RCC_ClkInitStruct.ClockType = (RCC_CLOCKTYPE_SYSCLK | RCC_CLOCKTYPE_HCLK | RCC_CLOCKTYPE_PCLK1 | RCC_CLOCKTYPE_PCLK2);
  RCC_ClkInitStruct.SYSCLKSource = RCC_SYSCLKSOURCE_PLLCLK; // SysCLK = 200 MHz
  RCC_ClkInitStruct.AHBCLKDivider = RCC_SYSCLK_DIV1;	// AHB CLK = 200 MHz
  RCC_ClkInitStruct.APB1CLKDivider = RCC_HCLK_DIV4;		// APB1 CLK = 50 MHz
  RCC_ClkInitStruct.APB2CLKDivider = RCC_HCLK_DIV2;		// APB2 CLK = 100 MHz

  ret = HAL_RCC_ClockConfig(&RCC_ClkInitStruct, FLASH_LATENCY_6);
  if(ret != HAL_OK)
  {
    while(1) { ; }
  }
}

/**
  * @brief  Configure the MPU attributes
  * @param  None
  * @retval None
  */
static void MPU_Config(void)
{
  MPU_Region_InitTypeDef MPU_InitStruct;

  /* Disable the MPU */
  HAL_MPU_Disable();

  /* Configure the MPU as Strongly ordered for not defined regions */
  MPU_InitStruct.Enable = MPU_REGION_ENABLE;
  MPU_InitStruct.BaseAddress = 0x00;
  MPU_InitStruct.Size = MPU_REGION_SIZE_4GB;
  MPU_InitStruct.AccessPermission = MPU_REGION_NO_ACCESS;
  MPU_InitStruct.IsBufferable = MPU_ACCESS_NOT_BUFFERABLE;
  MPU_InitStruct.IsCacheable = MPU_ACCESS_NOT_CACHEABLE;
  MPU_InitStruct.IsShareable = MPU_ACCESS_SHAREABLE;
  MPU_InitStruct.Number = MPU_REGION_NUMBER0;
  MPU_InitStruct.TypeExtField = MPU_TEX_LEVEL0;
  MPU_InitStruct.SubRegionDisable = 0x87;
  MPU_InitStruct.DisableExec = MPU_INSTRUCTION_ACCESS_DISABLE;

  HAL_MPU_ConfigRegion(&MPU_InitStruct);

  /* Configure the MPU attributes as WT for SDRAM */
  MPU_InitStruct.Enable = MPU_REGION_ENABLE;
  MPU_InitStruct.BaseAddress = 0xC0000000;
  MPU_InitStruct.Size = MPU_REGION_SIZE_32MB;
  MPU_InitStruct.AccessPermission = MPU_REGION_FULL_ACCESS;
  MPU_InitStruct.IsBufferable = MPU_ACCESS_NOT_BUFFERABLE;
  MPU_InitStruct.IsCacheable = MPU_ACCESS_CACHEABLE;
  MPU_InitStruct.IsShareable = MPU_ACCESS_NOT_SHAREABLE;
  MPU_InitStruct.Number = MPU_REGION_NUMBER1;
  MPU_InitStruct.TypeExtField = MPU_TEX_LEVEL0;
  MPU_InitStruct.SubRegionDisable = 0x00;
  MPU_InitStruct.DisableExec = MPU_INSTRUCTION_ACCESS_ENABLE;

  HAL_MPU_ConfigRegion(&MPU_InitStruct);

  /* Configure the MPU QSPI flash */
  MPU_InitStruct.Enable = MPU_REGION_ENABLE;
  MPU_InitStruct.BaseAddress = 0x90000000;
  MPU_InitStruct.Size = MPU_REGION_SIZE_64MB;
  MPU_InitStruct.AccessPermission = MPU_REGION_FULL_ACCESS;
  MPU_InitStruct.IsBufferable = MPU_ACCESS_NOT_BUFFERABLE;
  MPU_InitStruct.IsCacheable = MPU_ACCESS_CACHEABLE;
  MPU_InitStruct.IsShareable = MPU_ACCESS_NOT_SHAREABLE;
  MPU_InitStruct.Number = MPU_REGION_NUMBER2;
  MPU_InitStruct.TypeExtField = MPU_TEX_LEVEL0;
  MPU_InitStruct.SubRegionDisable = 0x0;
  MPU_InitStruct.DisableExec = MPU_INSTRUCTION_ACCESS_ENABLE;

  HAL_MPU_ConfigRegion(&MPU_InitStruct);

  /* Configure the MPU attributes FMC control registers */
  MPU_InitStruct.Enable = MPU_REGION_ENABLE;
  MPU_InitStruct.BaseAddress = 0xA0000000;
  MPU_InitStruct.Size = MPU_REGION_SIZE_8KB;
  MPU_InitStruct.AccessPermission = MPU_REGION_FULL_ACCESS;
  MPU_InitStruct.IsBufferable = MPU_ACCESS_BUFFERABLE;
  MPU_InitStruct.IsCacheable = MPU_ACCESS_NOT_CACHEABLE;
  MPU_InitStruct.IsShareable = MPU_ACCESS_SHAREABLE;
  MPU_InitStruct.Number = MPU_REGION_NUMBER3;
  MPU_InitStruct.TypeExtField = MPU_TEX_LEVEL0;
  MPU_InitStruct.SubRegionDisable = 0x0;
  MPU_InitStruct.DisableExec = MPU_INSTRUCTION_ACCESS_DISABLE;

  HAL_MPU_ConfigRegion(&MPU_InitStruct);

  /* Enable the MPU */
  HAL_MPU_Enable(MPU_PRIVILEGED_DEFAULT);
}

#ifdef  USE_FULL_ASSERT

/**
  * @brief  Reports the name of the source file and the source line number
  *         where the assert_param error has occurred.
  * @param  file: pointer to the source file name
  * @param  line: assert_param error line source number
  * @retval None
  */
void assert_failed(uint8_t* file, uint32_t line)
{
  /* User can add his own implementation to report the file name and line number,
     ex: printf("Wrong parameters value: file %s on line %d\r\n", file, line) */

  /* Infinite loop */
  while (1)
  {
  }
}
#endif /* USE_FULL_ASSERT */

/**
  * @brief  CPU L1-Cache enable.
  * @param  None
  * @retval None
  */
static void CPU_CACHE_Enable(void)
{
  /* Enable I-Cache */
  SCB_EnableICache();

  /* Enable D-Cache */
  SCB_EnableDCache();
}

/**
  * @brief  Check for user input
  * @param  None
* @retval Input state (1 : active / 0 : Inactive)
  */
uint8_t CheckForUserInput(void)
{
  if(BSP_PB_GetState(BUTTON_WAKEUP) == GPIO_PIN_SET)
  {
    while (BSP_PB_GetState(BUTTON_WAKEUP) == GPIO_PIN_SET);
    return 1 ;
  }
  return 0;
}

/**
  * @brief  EXTI line detection callbacks.
  * @param  GPIO_Pin: Specifies the pins connected EXTI line
  * @retval None
  */
void HAL_GPIO_EXTI_Callback(uint16_t GPIO_Pin)
{
	BSP_LED_Toggle(LED_GREEN);
}

void Task1(void *argument)
{
  /* USER CODE BEGIN 5 */
  CAN_OBD2_MSGQUEUE_OBJ_t queue_data;
  osStatus_t status = osOK;
  uint32_t size;
  uint8_t pid;

  float fvalue;
  uint32_t ui32value;
  uint8_t* obd_response[8];

  /* Infinite loop */
  for(;;)
  {
	osDelay(100);
    //size = osMessageQueueGetCount(mid_MsgQueue);
    //if (size != 0)
	status = osMessageQueueGet(mid_MsgQueue, &queue_data, NULL, osWaitForever);
    if (status == osOK){
    	//pid = queue_data.pid - 0x40;	// ECU responds same as query, except that 40h is added to the service value (PID)
    	pid = queue_data.pid;

    	switch (pid){
    	case OBD2_PID_PIDS_SUPPORTED_01_20:
    		break;
    	case OBD2_PID_FUEL_SYS_STATUS:
    		break;
    	case OBD2_PID_ENGINE_COOLANT_TEMP:
    		ui32value = OBD2DecodeEngineCoolantTemp(queue_data.OBDData);
    		sprintf(obd_response, "%d", ui32value);
    		BSP_LCD_DisplayStringAt(90, 105 + 160 + 4, obd_response, LEFT_MODE);
    		break;
    	case OBD2_PID_FUEL_PRESSURE:
    		break;
    	case OBD2_PID_ENGINE_SPEED:
    		ui32value = OBD2DecodeEngineSpeed(queue_data.OBDData);
    		sprintf(obd_response, "%d", ui32value);
    		BSP_LCD_DisplayStringAt(90, 145, obd_response, LEFT_MODE);
    		break;
    	case OBD2_PID_VEHICLE_SPEED:
    		ui32value = OBD2DecodeVehicleSpeed(queue_data.OBDData);
    		sprintf(obd_response, "%d", ui32value);
    		BSP_LCD_DisplayStringAt(BSP_LCD_GetXSize()/3+2+90, 145, obd_response, LEFT_MODE);

    		break;
    	case OBD2_PID_ENGINE_LOAD:
    		fvalue = OBD2DecodeEngineLoad(queue_data.OBDData);
    		sprintf(obd_response, "%.1f %", fvalue);
    		BSP_LCD_DisplayStringAt(2*BSP_LCD_GetXSize()/3+2+90, 145, obd_response, LEFT_MODE);

    		break;
    	case OBD2_PID_INTAKE_AIR_TEMP:
    		ui32value = OBD2DecodeIntakeAirTemp(queue_data.OBDData);
    		sprintf(obd_response, "%d", ui32value);
    		BSP_LCD_DisplayStringAt(2*BSP_LCD_GetXSize()/3+2+90, 105 + 160 + 4, obd_response, LEFT_MODE);
    		break;
    	case OBD2_PID_THROTTLE_POSITION:
    		break;
    	case OBD2_PID_ENGINE_OIL_TEMP:
    		ui32value = OBD2DecodeOilTemp(queue_data.OBDData);
    		sprintf(obd_response, "%d", ui32value);
    		BSP_LCD_DisplayStringAt(BSP_LCD_GetXSize()/3+2+90, 105 + 160 + 4, obd_response, LEFT_MODE);
    		break;
    	case OBD2_PID_ENGINE_FUEL_RATE:
    		break;
    	default:
    		break;
    	}

    }
  }

}

void Task2(void *argument)
{
  /* USER CODE BEGIN 5 */
  CAN_OBD2_MSGQUEUE_OBJ_t queue_element;
  uint32_t size;
  osStatus_t osstatus;

  /* Infinite loop */
  for(;;)
  {
	  OBD2_SendQuery(0x01, OBD2_PID_ENGINE_LOAD);
	  osDelay(50);
	  OBD2_SendQuery(0x01, OBD2_PID_ENGINE_COOLANT_TEMP);
	  osDelay(50);
	  OBD2_SendQuery(0x01, OBD2_PID_FUEL_PRESSURE);
	  osDelay(50);
	  OBD2_SendQuery(0x01, OBD2_PID_ENGINE_SPEED);
	  osDelay(50);
	  OBD2_SendQuery(0x01, OBD2_PID_VEHICLE_SPEED);
	  osDelay(50);
	  OBD2_SendQuery(0x01, OBD2_PID_INTAKE_AIR_TEMP);
	  osDelay(50);
	  OBD2_SendQuery(0x01, OBD2_PID_THROTTLE_POSITION);
	  osDelay(50);
	  OBD2_SendQuery(0x01, OBD2_PID_FUEL_TYPE);
	  osDelay(50);
	  OBD2_SendQuery(0x01, OBD2_PID_ENGINE_OIL_TEMP);
	  osDelay(50);
	  OBD2_SendQuery(0x01, OBD2_PID_ENGINE_FUEL_RATE);
	  osDelay(50);
  }
}

/* USER CODE END 4 */

void StartDefaultTask(void *argument)
{
  /* USER CODE BEGIN 5 */

  /* Infinite loop */
  for(;;)
  {
    osDelay(50);
    //osMessageQueueGet(mid_MsgQueue, &queue_element, 0U, 0U);
    //BSP_LCD_DisplayStringAt(0, BSP_LCD_GetYSize() / 2 + 50, (uint8_t *)"Default Task", CENTER_MODE);
    //BSP_LCD_DisplayStringAt(0, BSP_LCD_GetYSize() / 2 + 50, (uint8_t *)(queue_element.buffer), CENTER_MODE);
    osDelay(50);
  }
  /* USER CODE END 5 */
}

void Error_Handler(void)
{
  __disable_irq();
  while (1)
  {
  }
}
